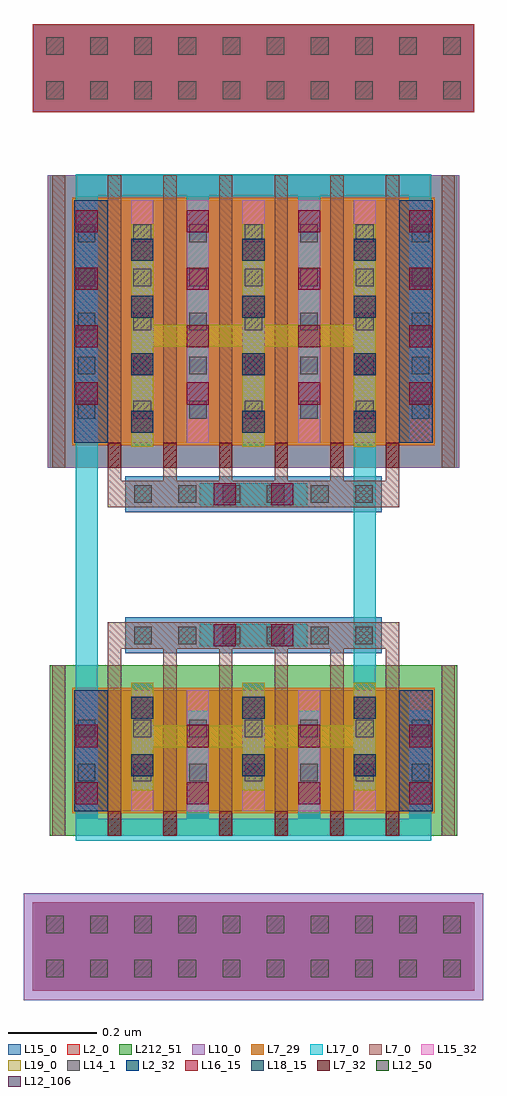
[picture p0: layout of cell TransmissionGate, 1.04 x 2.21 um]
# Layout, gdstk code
import gdstk
lib = gdstk.Library(unit=1e-6, precision=1e-09)
def R(c, l, rs):  # rectangles x0, y0, x1, y1
    for r in rs: c.add(gdstk.rectangle(r[:2], r[2:], *l))
def A(c, l, x, y, w, h, nx, ny, dx, dy):  # array of equal rectangles
    R(c, l, [(x+i*dx, y+j*dy, x+i*dx+w, y+j*dy+h) for i in range(nx) for j in range(ny)])
def P(c, l, *ps):  # polygons
    for p in ps: c.add(gdstk.Polygon(p, *l))
L2_0 = (2, 0)
L2_32 = (2, 32)
L7_0 = (7, 0)
L7_29 = (7, 29)
L7_32 = (7, 32)
L10_0 = (10, 0)
L12_50 = (12, 50)
L12_106 = (12, 106)
L14_1 = (14, 1)
L15_0 = (15, 0)
L15_32 = (15, 32)
L16_15 = (16, 15)
L17_0 = (17, 0)
L18_15 = (18, 15)
L19_0 = (19, 0)
L212_51 = (212, 51)

viamet12met2onnmosoutput = lib.new_cell('ViaMet12Met2OnNMOSOutputInTransmissionGate')
R(viamet12met2onnmosoutput, L15_0, [(-0.025,-0.122,0.025,0.122)])
R(viamet12met2onnmosoutput, L16_15, [(-0.025,-0.09,0.025,-0.04), (-0.025,0.04,0.025,0.09)])
R(viamet12met2onnmosoutput, L17_0, [(-0.025,-0.122,0.025,0.122)])

pbodycontactintransmissi = lib.new_cell('PbodycontactinTransmissionGate')
R(pbodycontactintransmissi, L2_0, [(-0.5,-0.1,0.5,0.1)])
R(pbodycontactintransmissi, L10_0, [(-0.521,-0.121,0.521,0.121)])
A(pbodycontactintransmissi, L14_1, -0.47, -0.07, 0.04, 0.04, 10, 2, 0.1, 0.1)
R(pbodycontactintransmissi, L15_0, [(-0.5,-0.1,0.5,0.1)])

nbodycontactintransmissi = lib.new_cell('NbodycontactinTransmissionGate')
R(nbodycontactintransmissi, L2_0, [(-0.5,-0.1,0.5,0.1)])
A(nbodycontactintransmissi, L14_1, -0.47, -0.07, 0.04, 0.04, 10, 2, 0.1, 0.1)
R(nbodycontactintransmissi, L15_0, [(-0.5,-0.1,0.5,0.1)])

pmosintransmissiongate = lib.new_cell('PMOSInTransmissionGate')
R(pmosintransmissiongate, L2_0, [(-0.406,-0.275,0.406,0.275)])
R(pmosintransmissiongate, L2_32, [(-0.406,-0.275,-0.33,0.275), (0.33,-0.275,0.406,0.275)])
A(pmosintransmissiongate, L7_0, -0.456, -0.331, 0.03, 0.662, 8, 1, 0.126, 0)
R(pmosintransmissiongate, L7_29, [(-0.411,-0.28,0.411,0.28)])
A(pmosintransmissiongate, L7_32, -0.33, -0.331, 0.03, 0.056, 6, 1, 0.126, 0)
R(pmosintransmissiongate, L10_0, [(-0.466,-0.331,0.466,0.331)])
P(pmosintransmissiongate, L12_50, [(0,0),(0,0),(0,0),(0,0)])
P(pmosintransmissiongate, L12_106, [(0,0),(0,0),(0,0),(0,0)])
A(pmosintransmissiongate, L14_1, -0.398, -0.22, 0.04, 0.04, 7, 5, 0.126, 0.1)
A(pmosintransmissiongate, L15_0, -0.403, -0.275, 0.05, 0.55, 7, 1, 0.126, 0)
A(pmosintransmissiongate, L15_32, -0.403, -0.275, 0.05, 0.55, 7, 1, 0.126, 0)
R(pmosintransmissiongate, L212_51, [(-0.462,-0.331,0.462,0.331)])

viamet22met3onnmosoutput = lib.new_cell('ViaMet22Met3OnNMOSOutputInTransmissionGate')
R(viamet22met3onnmosoutput, L17_0, [(-0.025,-0.122,0.025,0.122)])
R(viamet22met3onnmosoutput, L18_15, [(-0.025,-0.09,0.025,-0.04), (-0.025,0.04,0.025,0.09)])
R(viamet22met3onnmosoutput, L19_0, [(-0.025,-0.122,0.025,0.122)])

viapoly2met1onnmoscontro = lib.new_cell('ViaPoly2Met1OnNMOSControlInTransmissionGate')
R(viapoly2met1onnmoscontro, L7_0, [(-0.28,-0.03,0.28,0.03)])
A(viapoly2met1onnmoscontro, L14_1, -0.27, -0.02, 0.04, 0.04, 6, 1, 0.1, 0)
R(viapoly2met1onnmoscontro, L15_0, [(-0.291,-0.041,0.291,0.041)])

viamet12met2onnmoscontro = lib.new_cell('ViaMet12Met2OnNMOSControlInTransmissionGate')
R(viamet12met2onnmoscontro, L15_0, [(-0.122,-0.025,0.122,0.025)])
R(viamet12met2onnmoscontro, L16_15, [(-0.09,-0.025,-0.04,0.025), (0.04,-0.025,0.09,0.025)])
R(viamet12met2onnmoscontro, L17_0, [(-0.122,-0.025,0.122,0.025)])

viamet12met2onpmosoutput = lib.new_cell('ViaMet12Met2OnPMOSOutputInTransmissionGate')
R(viamet12met2onpmosoutput, L15_0, [(-0.025,-0.252,0.025,0.252)])
A(viamet12met2onpmosoutput, L16_15, -0.025, -0.22, 0.05, 0.05, 1, 4, 0, 0.13)
R(viamet12met2onpmosoutput, L17_0, [(-0.025,-0.252,0.025,0.252)])

viamet12met2onpmoscontro = lib.new_cell('ViaMet12Met2OnPMOSControlInTransmissionGate')
R(viamet12met2onpmoscontro, L15_0, [(-0.122,-0.025,0.122,0.025)])
R(viamet12met2onpmoscontro, L16_15, [(-0.09,-0.025,-0.04,0.025), (0.04,-0.025,0.09,0.025)])
R(viamet12met2onpmoscontro, L17_0, [(-0.122,-0.025,0.122,0.025)])

viapoly2met1onpmoscontro = lib.new_cell('ViaPoly2Met1OnPMOSControlInTransmissionGate')
R(viapoly2met1onpmoscontro, L7_0, [(-0.28,-0.03,0.28,0.03)])
A(viapoly2met1onpmoscontro, L14_1, -0.27, -0.02, 0.04, 0.04, 6, 1, 0.1, 0)
R(viapoly2met1onpmoscontro, L15_0, [(-0.291,-0.041,0.291,0.041)])

viamet22met3onpmosoutput = lib.new_cell('ViaMet22Met3OnPMOSOutputInTransmissionGate')
R(viamet22met3onpmosoutput, L17_0, [(-0.025,-0.252,0.025,0.252)])
A(viamet22met3onpmosoutput, L18_15, -0.025, -0.22, 0.05, 0.05, 1, 4, 0, 0.13)
R(viamet22met3onpmosoutput, L19_0, [(-0.025,-0.252,0.025,0.252)])

nmosintransmissiongate = lib.new_cell('NMOSInTransmissionGate')
R(nmosintransmissiongate, L2_0, [(-0.406,-0.137,0.406,0.137)])
R(nmosintransmissiongate, L2_32, [(-0.406,-0.137,-0.33,0.137), (0.33,-0.137,0.406,0.137)])
A(nmosintransmissiongate, L7_0, -0.456, -0.193, 0.03, 0.386, 8, 1, 0.126, 0)
R(nmosintransmissiongate, L7_29, [(-0.411,-0.142,0.411,0.142)])
A(nmosintransmissiongate, L7_32, -0.33, -0.193, 0.03, 0.056, 6, 1, 0.126, 0)
P(nmosintransmissiongate, L12_50, [(0,0),(0,0),(0,0),(0,0)])
P(nmosintransmissiongate, L12_106, [(0,0),(0,0),(0,0),(0,0)])
A(nmosintransmissiongate, L14_1, -0.398, -0.07, 0.04, 0.04, 7, 2, 0.126, 0.1)
A(nmosintransmissiongate, L15_0, -0.403, -0.137, 0.05, 0.274, 7, 1, 0.126, 0)
A(nmosintransmissiongate, L15_32, -0.403, -0.137, 0.05, 0.274, 7, 1, 0.126, 0)
R(nmosintransmissiongate, L212_51, [(-0.462,-0.193,0.462,0.193)])

transmissiongate = lib.new_cell('TransmissionGate')
transmissiongate.add(gdstk.FlexPath([(-0.403,1.725),(0.403,1.725)], 0.05, ends="flush", simple_path=True, layer=17, datatype=0))  # L17_0
transmissiongate.add(gdstk.FlexPath([(-0.252,0.476),(0.252,0.476)], 0.05, ends="flush", simple_path=True, layer=19, datatype=0))  # L19_0
transmissiongate.add(gdstk.FlexPath([(-0.315,0.705),(0.315,0.705)], 0.06, ends="flush", simple_path=True, layer=7, datatype=0))  # L7_0
transmissiongate.add(gdstk.FlexPath([(-0.315,0.444),(-0.315,0.735)], 0.03, ends="flush", simple_path=True, layer=7, datatype=0))  # L7_0
transmissiongate.add(gdstk.FlexPath([(-0.189,0.444),(-0.189,0.735)], 0.03, ends="flush", simple_path=True, layer=7, datatype=0))  # L7_0
transmissiongate.add(gdstk.FlexPath([(-0.063,0.444),(-0.063,0.735)], 0.03, ends="flush", simple_path=True, layer=7, datatype=0))  # L7_0
transmissiongate.add(gdstk.FlexPath([(0.063,0.444),(0.063,0.735)], 0.03, ends="flush", simple_path=True, layer=7, datatype=0))  # L7_0
transmissiongate.add(gdstk.FlexPath([(0.189,0.444),(0.189,0.735)], 0.03, ends="flush", simple_path=True, layer=7, datatype=0))  # L7_0
transmissiongate.add(gdstk.FlexPath([(0.315,0.444),(0.315,0.735)], 0.03, ends="flush", simple_path=True, layer=7, datatype=0))  # L7_0
transmissiongate.add(gdstk.FlexPath([(-0.378,1.416),(-0.378,0.444)], 0.05, ends="flush", simple_path=True, layer=17, datatype=0))  # L17_0
transmissiongate.add(gdstk.FlexPath([(-0.403,0.265),(0.403,0.265)], 0.05, ends="flush", simple_path=True, layer=17, datatype=0))  # L17_0
transmissiongate.add(gdstk.FlexPath([(-0.122,1.025),(0.122,1.025)], 0.082, ends="flush", simple_path=True, layer=15, datatype=0))  # L15_0
transmissiongate.add(gdstk.FlexPath([(0.252,1.416),(0.252,0.444)], 0.05, ends="flush", simple_path=True, layer=17, datatype=0))  # L17_0
transmissiongate.add(gdstk.FlexPath([(-0.122,0.705),(0.122,0.705)], 0.082, ends="flush", simple_path=True, layer=15, datatype=0))  # L15_0
transmissiongate.add(gdstk.FlexPath([(-0.315,1.416),(-0.315,0.995)], 0.03, ends="flush", simple_path=True, layer=7, datatype=0))  # L7_0
transmissiongate.add(gdstk.FlexPath([(-0.189,1.416),(-0.189,0.995)], 0.03, ends="flush", simple_path=True, layer=7, datatype=0))  # L7_0
transmissiongate.add(gdstk.FlexPath([(-0.063,1.416),(-0.063,0.995)], 0.03, ends="flush", simple_path=True, layer=7, datatype=0))  # L7_0
transmissiongate.add(gdstk.FlexPath([(0.063,1.416),(0.063,0.995)], 0.03, ends="flush", simple_path=True, layer=7, datatype=0))  # L7_0
transmissiongate.add(gdstk.FlexPath([(0.189,1.416),(0.189,0.995)], 0.03, ends="flush", simple_path=True, layer=7, datatype=0))  # L7_0
transmissiongate.add(gdstk.FlexPath([(0.315,1.416),(0.315,0.995)], 0.03, ends="flush", simple_path=True, layer=7, datatype=0))  # L7_0
transmissiongate.add(gdstk.FlexPath([(-0.315,1.025),(0.315,1.025)], 0.06, ends="flush", simple_path=True, layer=7, datatype=0))  # L7_0
transmissiongate.add(gdstk.FlexPath([(-0.252,1.384),(0.252,1.384)], 0.05, ends="flush", simple_path=True, layer=19, datatype=0))  # L19_0
transmissiongate.add(gdstk.Reference(viamet12met2onnmosoutput, (-0.252,0.476)))
transmissiongate.add(gdstk.Reference(viamet12met2onnmosoutput, (0,0.476)))
transmissiongate.add(gdstk.Reference(viamet12met2onnmosoutput, (0.252,0.476)))
transmissiongate.add(gdstk.Reference(viamet12met2onnmosoutput, (-0.378,0.412)))
transmissiongate.add(gdstk.Reference(viamet12met2onnmosoutput, (-0.126,0.412)))
transmissiongate.add(gdstk.Reference(viamet12met2onnmosoutput, (0.126,0.412)))
transmissiongate.add(gdstk.Reference(viamet12met2onnmosoutput, (0.378,0.412)))
transmissiongate.add(gdstk.Reference(pbodycontactintransmissi, (0,0)))
transmissiongate.add(gdstk.Reference(nbodycontactintransmissi, (0,1.99)))
transmissiongate.add(gdstk.Reference(pmosintransmissiongate, (0,1.416)))
transmissiongate.add(gdstk.Reference(viamet22met3onnmosoutput, (-0.252,0.476)))
transmissiongate.add(gdstk.Reference(viamet22met3onnmosoutput, (0,0.476)))
transmissiongate.add(gdstk.Reference(viamet22met3onnmosoutput, (0.252,0.476)))
transmissiongate.add(gdstk.Reference(viapoly2met1onnmoscontro, (0,0.705)))
transmissiongate.add(gdstk.Reference(viamet12met2onnmoscontro, (0,0.705)))
transmissiongate.add(gdstk.Reference(viamet12met2onpmosoutput, (-0.252,1.384)))
transmissiongate.add(gdstk.Reference(viamet12met2onpmosoutput, (0,1.384)))
transmissiongate.add(gdstk.Reference(viamet12met2onpmosoutput, (0.252,1.384)))
transmissiongate.add(gdstk.Reference(viamet12met2onpmosoutput, (-0.378,1.448)))
transmissiongate.add(gdstk.Reference(viamet12met2onpmosoutput, (-0.126,1.448)))
transmissiongate.add(gdstk.Reference(viamet12met2onpmosoutput, (0.126,1.448)))
transmissiongate.add(gdstk.Reference(viamet12met2onpmosoutput, (0.378,1.448)))
transmissiongate.add(gdstk.Reference(viamet12met2onpmoscontro, (0,1.025)))
transmissiongate.add(gdstk.Reference(viapoly2met1onpmoscontro, (0,1.025)))
transmissiongate.add(gdstk.Reference(viamet22met3onpmosoutput, (-0.252,1.384)))
transmissiongate.add(gdstk.Reference(viamet22met3onpmosoutput, (0,1.384)))
transmissiongate.add(gdstk.Reference(viamet22met3onpmosoutput, (0.252,1.384)))
transmissiongate.add(gdstk.Reference(nmosintransmissiongate, (0,0.444)))

lib.write_gds('TransmissionGate.gds')
